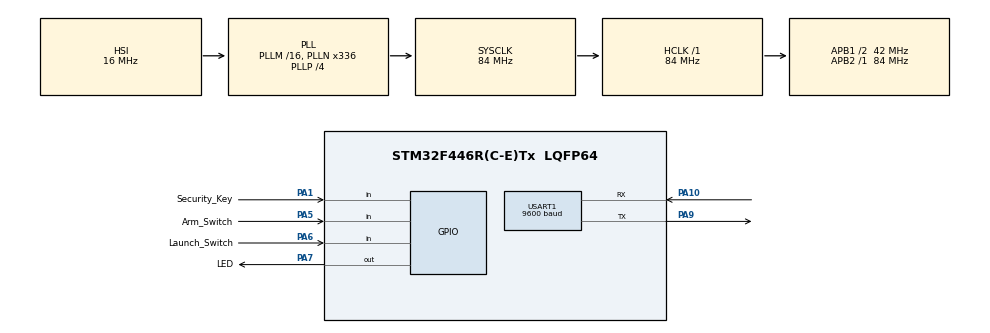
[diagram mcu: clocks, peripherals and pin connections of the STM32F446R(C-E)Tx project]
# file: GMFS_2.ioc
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Dma.Request0=USART1_RX
Dma.USART1_RX.0.Direction=DMA_PERIPH_TO_MEMORY
Dma.USART1_RX.0.FIFOMode=DMA_FIFOMODE_DISABLE
Dma.USART1_RX.0.Instance=DMA2_Stream2
Dma.USART1_RX.0.MemDataAlignment=DMA_MDATAALIGN_BYTE
Dma.USART1_RX.0.MemInc=DMA_MINC_ENABLE
Dma.USART1_RX.0.Mode=DMA_CIRCULAR
Dma.USART1_RX.0.PeriphDataAlignment=DMA_PDATAALIGN_BYTE
Dma.USART1_RX.0.PeriphInc=DMA_PINC_DISABLE
Dma.USART1_RX.0.Priority=DMA_PRIORITY_LOW
Mcu.Family=STM32F4
Mcu.Name=STM32F446R(C-E)Tx
Mcu.Package=LQFP64
NVIC.DMA2_Stream2_IRQn=true\:0\:0\:false\:false\:true\:false\:true\:true
NVIC.PriorityGroup=NVIC_PRIORITYGROUP_0
NVIC.USART1_IRQn=true\:0\:0\:false\:false\:true\:true\:true\:true
PA1.GPIO_Label=Security_Key
PA1.Signal=GPIO_Input
PA10.Mode=Asynchronous
PA10.Signal=USART1_RX
PA13.Mode=Serial_Wire
PA13.Signal=SYS_JTMS-SWDIO
PA14.Mode=Serial_Wire
PA14.Signal=SYS_JTCK-SWCLK
PA5.GPIO_Label=Arm_Switch
PA5.Signal=GPIO_Input
PA6.GPIO_Label=Launch_Switch
PA6.Signal=GPIO_Input
PA7.GPIO_Label=LED
PA7.Signal=GPIO_Output
PA9.Mode=Asynchronous
PA9.Signal=USART1_TX
PC14-OSC32_IN.Mode=LSE-External-Oscillator
PC14-OSC32_IN.Signal=RCC_OSC32_IN
PC15-OSC32_OUT.Mode=LSE-External-Oscillator
PC15-OSC32_OUT.Signal=RCC_OSC32_OUT
PH0-OSC_IN.Mode=HSE-External-Oscillator
PH0-OSC_IN.Signal=RCC_OSC_IN
PH1-OSC_OUT.Mode=HSE-External-Oscillator
PH1-OSC_OUT.Signal=RCC_OSC_OUT
ProjectManager.HeapSize=0x200
ProjectManager.StackSize=0x400
ProjectManager.TargetToolchain=STM32CubeIDE
RCC.48MHZClocksFreq_Value=84000000
RCC.AHBFreq_Value=84000000
RCC.APB1CLKDivider=RCC_HCLK_DIV2
RCC.APB1Freq_Value=42000000
RCC.APB1TimFreq_Value=84000000
RCC.APB2Freq_Value=84000000
RCC.APB2TimFreq_Value=84000000
RCC.CortexFreq_Value=84000000
RCC.FLatency-AdvancedSettings=FLASH_LATENCY_2
RCC.HCLKFreq_Value=84000000
RCC.HSE_VALUE=8000000
RCC.HSI_VALUE=16000000
RCC.PLLN=336
RCC.PLLP=RCC_PLLP_DIV4
RCC.SYSCLKFreq_VALUE=84000000
RCC.SYSCLKSource=RCC_SYSCLKSOURCE_PLLCLK
RCC.USBFreq_Value=168000000
RCC.VCOOutputFreq_Value=336000000
USART1.BaudRate=9600
USART1.VirtualMode=VM_ASYNC
board=NUCLEO-F446RE

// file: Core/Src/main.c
/* USER CODE BEGIN Header */
/**
  ******************************************************************************
  * @file           : main.c
  * @brief          : Main program body
  ******************************************************************************
  * @attention
  *
  * Copyright (c) 2023 STMicroelectronics.
  * All rights reserved.
  *
  * This software is licensed under terms that can be found in the LICENSE file
  * in the root directory of this software component.
  * If no LICENSE file comes with this software, it is provided AS-IS.
  *
  ******************************************************************************
  */
/* USER CODE END Header */
#include "main.h"

/* USER CODE BEGIN Includes */
#include<stdbool.h>
#include<stdlib.h>
/* USER CODE END Includes */

UART_HandleTypeDef huart1;
DMA_HandleTypeDef hdma_usart1_rx;

void SystemClock_Config(void);
static void MX_GPIO_Init(void);
static void MX_DMA_Init(void);
static void MX_USART1_UART_Init(void);

/* USER CODE BEGIN 0 */
char rx_data=0;
char tx_data=0;
bool Sec_key = 0, Arm_switch = 0, Ign_switch = 0;
bool seq_flag = 0;
bool ignition = 0;
//GMFS status Signals
char key='F';
char arm='B';
char isu_check='D';
char kill='K';
char ignition_switch='I';
char launch='L';
void seq_check()
	{
		if(HAL_GPIO_ReadPin(GPIOC, GPIO_PIN_3) == 0 && HAL_GPIO_ReadPin(GPIOC, GPIO_PIN_10)== 0 && HAL_GPIO_ReadPin(GPIOC, GPIO_PIN_8)== 0) seq_flag = 1;
		else if(Sec_key==0 && HAL_GPIO_ReadPin(GPIOC, GPIO_PIN_10)==1) seq_flag=0;
	}
/* USER CODE END 0 */

int main(void)
{

  /* MCU Configuration--------------------------------------------------------*/

  /* Reset of all peripherals, Initializes the Flash interface and the Systick. */
  HAL_Init();

  /* Configure the system clock */
  SystemClock_Config();

  /* Initialize all configured peripherals */
  MX_GPIO_Init();
  MX_DMA_Init();
  MX_USART1_UART_Init();
  /* USER CODE BEGIN 2 */
  HAL_UART_Receive_DMA(&huart1, rx_data, sizeof(rx_data));
  /* USER CODE END 2 */

  /* Infinite loop */
  while (1)
  {

    /* USER CODE BEGIN 3 */
	  seq_check();
	  	if(seq_flag ==1){
	  		if(HAL_GPIO_ReadPin(GPIOC, GPIO_PIN_3) == 1 || Sec_key == 1)
	  		{
	  			Sec_key=1;
	  			HAL_UART_Transmit(&huart1, key, sizeof(key), 100);
	  			tx_data=key;
	  			if(HAL_GPIO_ReadPin(GPIOC, GPIO_PIN_3) == 0 && Arm_switch == 0  ) {
	  				Sec_key = 0; // Notify the user to reset the inputs
	  				seq_flag = 0;
	  				Arm_switch = 0;
	  				Ign_switch = 0;
	  			}
	  			else{
	  				if(HAL_GPIO_ReadPin(GPIOC, GPIO_PIN_10)== 1 || Arm_switch == 1 ){
	  					Arm_switch = 1;
	  					tx_data=arm;
	  					HAL_UART_Transmit(&huart1, arm, sizeof(arm), 100);
	  					HAL_Delay(2000);
	  					tx_data=isu_check;
	  					HAL_UART_Transmit(&huart1, isu_check, sizeof(isu_check), 100);
	  					if(HAL_GPIO_ReadPin(GPIOC, GPIO_PIN_10) == 0) Arm_switch = 0;{
	  					if(HAL_GPIO_ReadPin(GPIOC, GPIO_PIN_8) == 1 || Ign_switch == 1){
	  						tx_data=ignition_switch;
	  						HAL_UART_Transmit(&huart1, ignition_switch, sizeof(ignition_switch), 100);
	  						Ign_switch = 1;
	  						HAL_Delay(2000);
	  						tx_data=launch;
	  						HAL_UART_Transmit(&huart1, launch, sizeof(launch), 100);

	  					}
	  					if(seq_flag == 0 && (rx_data=='I'||rx_data=='L')){
						HAL_GPIO_WritePin(GPIOC, GPIO_PIN_11,1);
						HAL_GPIO_WritePin(GPIOC, GPIO_PIN_7,1);
						HAL_Delay(2000);
						HAL_GPIO_WritePin(GPIOC, GPIO_PIN_7,0);
						HAL_GPIO_WritePin(GPIOC, GPIO_PIN_11,0);
	  						}
	  						else
	  						{
	  							Sec_key=0;
	  							Arm_switch = 0;
	  							seq_flag = 0;
	  						}
	  						}

	  				}
	  			}
	  		}
//	  	        if(HAL_GPIO_ReadPin(GPIOA, GPIO_PIN_7) == 1) //kill switch)
//	  		  	HAL_UART_Transmit(&huart1, kill, sizeof(kill), 100);

	      /* USER CODE END WHILE */

	      /* USER CODE BEGIN 3 */
	    }
	  	}
  /* USER CODE END 3 */
}

void SystemClock_Config(void)
{
  RCC_OscInitTypeDef RCC_OscInitStruct = {0};
  RCC_ClkInitTypeDef RCC_ClkInitStruct = {0};

  /** Configure the main internal regulator output voltage
  */
  __HAL_RCC_PWR_CLK_ENABLE();
  __HAL_PWR_VOLTAGESCALING_CONFIG(PWR_REGULATOR_VOLTAGE_SCALE3);

  /** Initializes the RCC Oscillators according to the specified parameters
  * in the RCC_OscInitTypeDef structure.
  */
  RCC_OscInitStruct.OscillatorType = RCC_OSCILLATORTYPE_HSI;
  RCC_OscInitStruct.HSIState = RCC_HSI_ON;
  RCC_OscInitStruct.HSICalibrationValue = RCC_HSICALIBRATION_DEFAULT;
  RCC_OscInitStruct.PLL.PLLState = RCC_PLL_ON;
  RCC_OscInitStruct.PLL.PLLSource = RCC_PLLSOURCE_HSI;
  RCC_OscInitStruct.PLL.PLLM = 16;
  RCC_OscInitStruct.PLL.PLLN = 336;
  RCC_OscInitStruct.PLL.PLLP = RCC_PLLP_DIV4;
  RCC_OscInitStruct.PLL.PLLQ = 2;
  RCC_OscInitStruct.PLL.PLLR = 2;
  if (HAL_RCC_OscConfig(&RCC_OscInitStruct) != HAL_OK)
  {
    Error_Handler();
  }

  /** Initializes the CPU, AHB and APB buses clocks
  */
  RCC_ClkInitStruct.ClockType = RCC_CLOCKTYPE_HCLK|RCC_CLOCKTYPE_SYSCLK
                              |RCC_CLOCKTYPE_PCLK1|RCC_CLOCKTYPE_PCLK2;
  RCC_ClkInitStruct.SYSCLKSource = RCC_SYSCLKSOURCE_PLLCLK;
  RCC_ClkInitStruct.AHBCLKDivider = RCC_SYSCLK_DIV1;
  RCC_ClkInitStruct.APB1CLKDivider = RCC_HCLK_DIV2;
  RCC_ClkInitStruct.APB2CLKDivider = RCC_HCLK_DIV1;

  if (HAL_RCC_ClockConfig(&RCC_ClkInitStruct, FLASH_LATENCY_2) != HAL_OK)
  {
    Error_Handler();
  }
}

static void MX_USART1_UART_Init(void)
{

  huart1.Instance = USART1;
  huart1.Init.BaudRate = 9600;
  huart1.Init.WordLength = UART_WORDLENGTH_8B;
  huart1.Init.StopBits = UART_STOPBITS_1;
  huart1.Init.Parity = UART_PARITY_NONE;
  huart1.Init.Mode = UART_MODE_TX_RX;
  huart1.Init.HwFlowCtl = UART_HWCONTROL_NONE;
  huart1.Init.OverSampling = UART_OVERSAMPLING_16;
  if (HAL_UART_Init(&huart1) != HAL_OK)
  {
    Error_Handler();
  }

}

static void MX_DMA_Init(void)
{

  /* DMA controller clock enable */
  __HAL_RCC_DMA2_CLK_ENABLE();

  /* DMA interrupt init */
  /* DMA2_Stream2_IRQn interrupt configuration */
  HAL_NVIC_SetPriority(DMA2_Stream2_IRQn, 0, 0);
  HAL_NVIC_EnableIRQ(DMA2_Stream2_IRQn);

}

static void MX_GPIO_Init(void)
{
  GPIO_InitTypeDef GPIO_InitStruct = {0};

  /* GPIO Ports Clock Enable */
  __HAL_RCC_GPIOC_CLK_ENABLE();
  __HAL_RCC_GPIOH_CLK_ENABLE();
  __HAL_RCC_GPIOA_CLK_ENABLE();

  /*Configure GPIO pin Output Level */
  HAL_GPIO_WritePin(GPIOC, LED_Pin|Buzzer_Pin, GPIO_PIN_RESET);

  /*Configure GPIO pins : Security_Key_Pin Ignition_Switch_Pin Arm_Switch_Pin */
  GPIO_InitStruct.Pin = Security_Key_Pin|Ignition_Switch_Pin|Arm_Switch_Pin;
  GPIO_InitStruct.Mode = GPIO_MODE_INPUT;
  GPIO_InitStruct.Pull = GPIO_NOPULL;
  HAL_GPIO_Init(GPIOC, &GPIO_InitStruct);

  /*Configure GPIO pins : LED_Pin Buzzer_Pin */
  GPIO_InitStruct.Pin = LED_Pin|Buzzer_Pin;
  GPIO_InitStruct.Mode = GPIO_MODE_OUTPUT_PP;
  GPIO_InitStruct.Pull = GPIO_NOPULL;
  GPIO_InitStruct.Speed = GPIO_SPEED_FREQ_LOW;
  HAL_GPIO_Init(GPIOC, &GPIO_InitStruct);

}

void Error_Handler(void)
{
  __disable_irq();
  while (1)
  {
  }
}
